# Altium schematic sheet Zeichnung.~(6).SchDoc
size A4

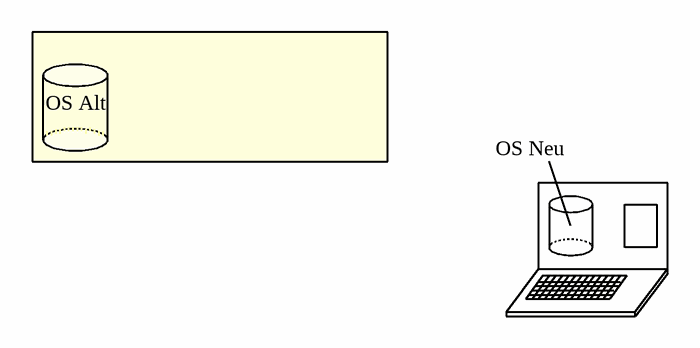
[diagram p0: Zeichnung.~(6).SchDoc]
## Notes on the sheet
- OS Alt
- OS Neu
